| IBIS file multipow.ibs created by s2ibis2 version 1.1
| North Carolina State University Electronics Research Laboratory  1995
[IBIS ver]   2.1
[File name]   multipow.ibs
[File Rev]   0
[Date]   April 1, 2001
[Source]   From MegaFLOPS Inc. layout and silicon models.
[Notes]   This is not an actual device. No one would buy it anyway.
[Disclaimer]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
[Copyright]   Copyright 2001 MegaFLOPS Inc.
|   Component MCM Driver Chip
[Component]   MCM Driver Chip
[Manufacturer]   MegaFLOPS Inc.
[Package]
| variable   typ   min   max
R_pkg   2.00m   1.00m   4.00m
L_pkg   0.20nH   0.10nH   0.40nH
C_pkg   2.00pF   1.00pF   4.00pF
[Pin]  signal_name   model_name   R_pin   L_pin   C_pin
1   gnd   GND
2   in1   input
3   in2   input
4   in3   input
5   enable   input
6   clmp_gnd   GND
7   clmp_vdd   POWER
8   NC   NC
9   out3   driver
10   out2   tristate_driver
11   out1   tristate_driver
12   vdd   POWER
[Pin Mapping]  pulldown_ref   pullup_ref   gnd_clamp_ref   power_clamp_ref
1   DRV_GND   NC
2   NC   NC   CLMP_GND   CLMP_VDD
3   NC   NC   CLMP_GND   CLMP_VDD
4   NC   NC   CLMP_GND   CLMP_VDD
5   NC   NC   CLMP_GND   CLMP_VDD
6   CLMP_GND   NC
7   NC   CLMP_VDD
8   NC   NC   NC   NC
9   DRV_GND   DRV_VDD   CLMP_GND   CLMP_VDD
10   DRV_GND   DRV_VDD   CLMP_GND   CLMP_VDD
11   DRV_GND   DRV_VDD   CLMP_GND   CLMP_VDD
12   NC   DRV_VDD
| Models and submodels in the file (3): input (Input), driver (Output), tristate_driver (3-state)
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|   Model input
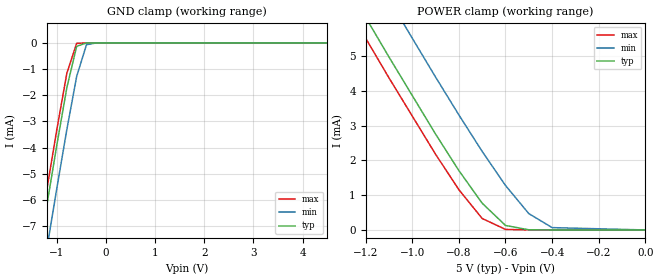
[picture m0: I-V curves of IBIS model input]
[Model]   input
Model_type   Input
C_comp   5.00pF   5.00pF   5.00pF
[Temperature Range]   27.00   100.00   0.000
[Pullup Reference]   3.30V   3.00V   3.60V
[Pulldown Reference]   0.000V   0.000V   0.000V
[POWER Clamp Reference]   5.00V   4.50V   5.50V
[GND Clamp Reference]   0.000V   0.000V   0.000V
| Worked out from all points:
|   GND clamp passes 1 mA (typ) near -0.71 V on its own axis
|   POWER clamp passes 1 mA (typ) near -0.72 V on its own axis
[GND_clamp]
| voltage   I(typ)   I(min)   I(max)
-5V       -51.06mA   -52.64mA   -50.49mA
-1.4V     -8.42mA    -10.08mA   -7.82mA
-1.2V     -6.12mA    -7.78mA    -5.52mA
-1V       -3.86mA    -5.51mA    -3.27mA
-800mV    -1.71mA    -3.31mA    -1.16mA
-600mV    -130uA     -1.28mA    -16.44uA
-400mV    -100nA     -67.71uA   -3.72nA
-200mV    -56.43pA   -180nA     -12.56pA
4.8V      9.2pA      3.88uA     8.2pA
5V        10.02pA    470uA      9pA
[POWER_clamp]
| voltage   I(typ)   I(min)   I(max)
-5V       51.06mA    52.64mA    50.49mA
-1.4V     8.42mA     10.08mA    7.82mA
-1.3V     7.26mA     8.93mA     6.66mA
-1.2V     6.12mA     7.78mA     5.52mA
-1.1V     4.98mA     6.64mA     4.38mA
-900mV    2.76mA     4.4mA      2.18mA
-800mV    1.71mA     3.31mA     1.16mA
-700mV    770uA      2.26mA     330uA
-600mV    130uA      1.28mA     16.45uA
-500mV    4.84uA     470uA      260nA
-400mV    100nA      67.71uA    3.72nA
0V        10.02pA    360pA      11pA
|   Model driver
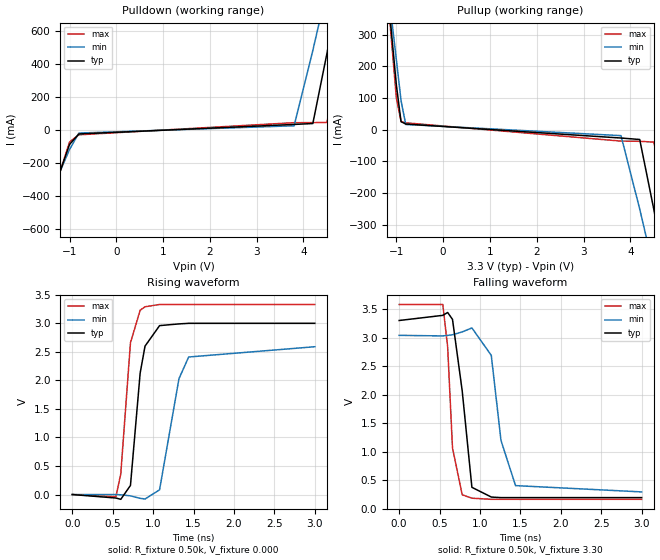
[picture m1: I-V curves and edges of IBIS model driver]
[Model]   driver
Model_type   Output
Polarity   Non-Inverting
C_comp   5.00pF   5.00pF   5.00pF
[Temperature Range]   27.00   100.00   0.000
[Pullup Reference]   3.30V   3.00V   3.60V
[Pulldown Reference]   0.000V   0.000V   0.000V
[POWER Clamp Reference]   5.00V   4.50V   5.50V
[GND Clamp Reference]   0.000V   0.000V   0.000V
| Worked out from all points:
|   slope of the pulldown table from 0 to 0.495 V, typ, clamps not added: 35.6 ohm
|   slope of the pullup table from 0 to 0.495 V, typ, clamps not added: 53 ohm
|   rising waveform, R_fixture 0.50k, V_fixture 0.000: 20-80 % time 121ps typ, 184ps min, 106ps max; typ from 0 V to 3 V
|   falling waveform, R_fixture 0.50k, V_fixture 3.30: 20-80 % time 110ps typ, 155ps min, 84.2ps max; typ from 3.3 V to 0.2 V
[Pulldown]
| voltage   I(typ)   I(min)   I(max)
-3.3V     -1.95A     -1.61A     -2.12A
-1.9V     -820mA     -710mA     -880mA
-1.7V     -660mA     -580mA     -700mA
-1V       -89.08mA   -120mA     -74.17mA
-800mV    -25.57mA   -20.11mA   -30.6mA
3.8V      32.13mA    24.11mA    42.78mA
4.2V      37.65mA    480mA      42.95mA
4.5V      460mA      850mA      44.43mA
4.7V      770mA      1.11A      290mA
4.9V      1.09A      1.36A      630mA
5.1V      1.4A       1.62A      980mA
6.6V      3.77A      3.52A      3.58A
[Pullup]
| voltage   I(typ)   I(min)   I(max)
-3.3V     3.79A      3.15A      4.12A
-1.5V     930mA      860mA      970mA
-1V       140mA      220mA      99.36mA
-900mV    25.45mA    91.47mA    25.83mA
-800mV    17.99mA    16.67mA    21.79mA
3.8V      -26.13mA   -18.61mA   -35.82mA
4.2V      -30.76mA   -250mA     -36.45mA
4.5V      -250mA     -440mA     -39.04mA
4.7V      -410mA     -570mA     -160mA
4.9V      -570mA     -700mA     -340mA
5.1V      -730mA     -830mA     -510mA
6.6V      -1.93A     -1.79A     -1.84A
[Ramp]
| variable   typ   min   max
dV/dt_r   1.80/0.11n   1.55/0.18n   2.00/88.55p
dV/dt_f   1.86/90.93p   1.64/0.15n   2.05/70.12p
R_load = 0.50k
[Rising Waveform]
R_fixture = 0.50k
V_fixture = 0.000
| time   V(typ)   V(min)   V(max)
0s        74.61uV    90.85uV    62.55uV
540ps     -61.15mV   150uV      -39.03mV
600ps     -84.06mV   -4.95mV    360mV
720ps     160mV      -23.03mV   2.66V
840ps     2.13V      -66.94mV   3.23V
900ps     2.6V       -77.93mV   3.29V
1.08ns    2.96V      82.8mV     3.33V
1.32ns    2.99V      2.03V      3.33V
1.44ns    3V         2.41V      3.33V
3ns       3V         2.59V      3.33V
[Falling Waveform]
R_fixture = 0.50k
V_fixture = 3.30
| time   V(typ)   V(min)   V(max)
0s        3.3V       3.04V      3.58V
540ps     3.39V      3.03V      3.58V
600ps     3.44V      3.04V      2.84V
660ps     3.32V      3.05V      1.07V
780ps     2.07V      3.1V       250mV
900ps     380mV      3.17V      190mV
1.14ns    210mV      2.69V      170mV
1.26ns    200mV      1.2V       170mV
1.44ns    200mV      410mV      170mV
3ns       200mV      300mV      170mV
|   Model tristate_driver
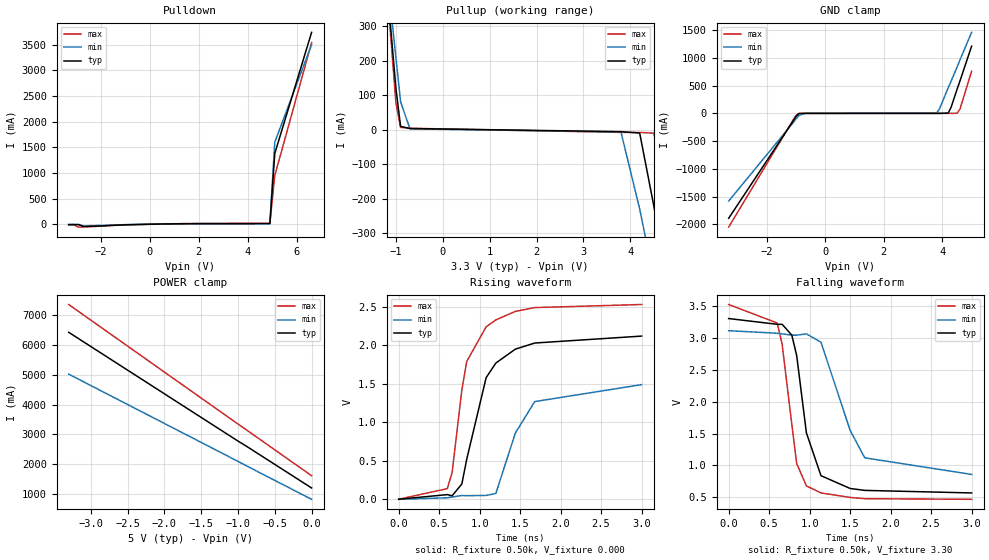
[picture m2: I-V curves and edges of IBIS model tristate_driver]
[Model]   tristate_driver
Model_type   3-state
Polarity   Non-Inverting
Enable   Active-Low
C_comp   5.00pF   5.00pF   5.00pF
[Temperature Range]   27.00   100.00   0.000
[Pullup Reference]   3.30V   3.00V   3.60V
[Pulldown Reference]   0.000V   0.000V   0.000V
[POWER Clamp Reference]   5.00V   4.50V   5.50V
[GND Clamp Reference]   0.000V   0.000V   0.000V
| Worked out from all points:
|   slope of the pulldown table from 0 to 0.495 V, typ, clamps not added: 102 ohm
|   slope of the pullup table from 0 to 0.495 V, typ, clamps not added: 229 ohm
|   GND clamp passes 1 mA (typ) near -0.82 V on its own axis
|   rising waveform, R_fixture 0.50k, V_fixture 0.000: 20-80 % time 323ps typ, 348ps min, 227ps max; typ from 0.002 V to 2.12 V
|   falling waveform, R_fixture 0.50k, V_fixture 3.30: 20-80 % time 188ps typ, 336ps min, 177ps max; typ from 3.3 V to 0.57 V
[Pulldown]
| voltage   I(typ)   I(min)   I(max)
-3.3V     -8.15mA    -3.31mA    -9.47mA
-3.1V     -7.77mA    -3.37mA    -8.97mA
-2.9V     -7.23mA    -3.43mA    -56.79mA
-2.7V     -45.32mA   -31.67mA   -53.63mA
-1.9V     -31.01mA   -22.85mA   -35.9mA
-1.5V     -20.79mA   -16.3mA    -23.49mA
-900mV    -9.68mA    -6.69mA    -11.59mA
500mV     4.89mA     3.3mA      5.97mA
1.5V      10.58mA    6.69mA     13.46mA
4.9V      13.9mA     8.37mA     17.4mA
5.1V      1.38A      1.6A       950mA
6.6V      3.74A      3.5A       3.54A
[Pullup]
| voltage   I(typ)   I(min)   I(max)
-3.3V     44.21mA    32.14mA    52.15mA
-1.7V     19.65mA    15.2mA     22.52mA
-1.5V     910mA      850mA      950mA
-1V       120mA      210mA      78.14mA
-900mV    9.8mA      81.15mA    6.77mA
-700mV    3.53mA     2.6mA      4.27mA
3.8V      -5.59mA    -6.48mA    -7.73mA
4.2V      -9.63mA    -230mA     -7.79mA
4.5V      -220mA     -430mA     -9.83mA
4.7V      -380mA     -550mA     -130mA
5.1V      -700mA     -810mA     -480mA
6.6V      -1.89A     -1.77A     -1.79A
[GND_clamp]
| voltage   I(typ)   I(min)   I(max)
-3.3V     -1.89A     -1.58A     -2.05A
-1.1V     -140mA     -170mA     -120mA
-1V       -58.03mA   -100mA     -36.74mA
-900mV    -3.15mA    -39.82mA   -1.05mA
-700mV    -180uA     -550uA     -91.44uA
3.8V      1.01nA     4.53mA     5.74pA
3.9V      48.08nA    77.73mA    6.38pA
4.2V      5.24mA     460mA      3.68nA
4.3V      110mA      580mA      260nA
4.5V      430mA      830mA      1.26mA
4.6V      580mA      960mA      71.98mA
5V        1.21A      1.46A      760mA
[POWER_clamp]
| voltage   I(typ)   I(min)   I(max)
-3.3V     6.42A      5.02A      7.35A
-1V       2.78A      2.1A       3.35A
-900mV    2.63A      1.97A      3.18A
0V        1.21A      830mA      1.62A
[Ramp]
| variable   typ   min   max
dV/dt_r   1.27/0.28n   0.89/0.36n   1.52/0.25n
dV/dt_f   1.64/0.20n   1.34/0.33n   1.85/0.16n
R_load = 0.50k
[Rising Waveform]
R_fixture = 0.50k
V_fixture = 0.000
| time   V(typ)   V(min)   V(max)
0s        2.3mV      1.57mV     2.76mV
600ps     62.83mV    21.76mV    140mV
660ps     47.72mV    31.35mV    350mV
780ps     200mV      51.08mV    1.42V
840ps     520mV      49.32mV    1.79V
1.08ns    1.58V      51.88mV    2.24V
1.2ns     1.77V      77.51mV    2.33V
1.44ns    1.95V      860mV      2.44V
1.68ns    2.03V      1.27V      2.49V
3ns       2.12V      1.49V      2.53V
[Falling Waveform]
R_fixture = 0.50k
V_fixture = 3.30
| time   V(typ)   V(min)   V(max)
0s        3.3V       3.11V      3.52V
600ps     3.21V      3.07V      3.23V
660ps     3.21V      3.06V      2.9V
780ps     3.04V      3.04V      1.64V
840ps     2.72V      3.04V      1.03V
960ps     1.51V      3.06V      680mV
1.14ns    840mV      2.93V      570mV
1.5ns     640mV      1.55V      500mV
1.68ns    610mV      1.12V      480mV
3ns       570mV      860mV      470mV
